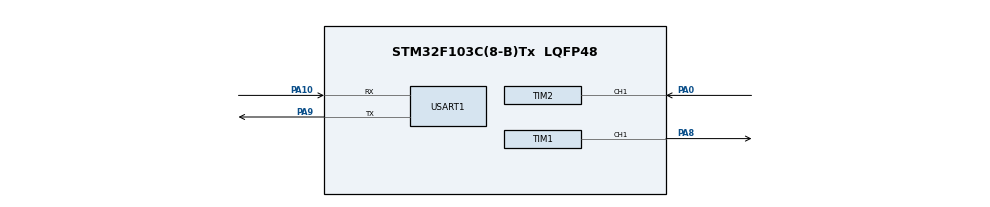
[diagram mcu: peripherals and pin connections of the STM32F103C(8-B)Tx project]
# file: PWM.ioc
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Mcu.Family=STM32F1
Mcu.Name=STM32F103C(8-B)Tx
Mcu.Package=LQFP48
NVIC.PriorityGroup=NVIC_PRIORITYGROUP_4
NVIC.TIM2_IRQn=true\:0\:0\:false\:false\:true\:true\:true\:true
PA0-WKUP.Signal=S_TIM2_CH1_ETR
PA10.Mode=Asynchronous
PA10.Signal=USART1_RX
PA13.Mode=Serial_Wire
PA13.Signal=SYS_JTMS-SWDIO
PA14.Mode=Serial_Wire
PA14.Signal=SYS_JTCK-SWCLK
PA8.Signal=S_TIM1_CH1
PA9.Mode=Asynchronous
PA9.Signal=USART1_TX
PD0-OSC_IN.Mode=HSE-External-Oscillator
PD0-OSC_IN.Signal=RCC_OSC_IN
PD1-OSC_OUT.Mode=HSE-External-Oscillator
PD1-OSC_OUT.Signal=RCC_OSC_OUT
ProjectManager.HeapSize=0x600
ProjectManager.StackSize=0x600
ProjectManager.TargetToolchain=MDK-ARM V5.32
RCC.APB1Freq_Value=8000000
RCC.APB2Freq_Value=8000000
SH.S_TIM1_CH1.0=TIM1_CH1,PWM Generation1 CH1
SH.S_TIM2_CH1_ETR.0=TIM2_CH1,PWM_Input_1
TIM1.Channel-PWM\ Generation1\ CH1=TIM_CHANNEL_1
TIM1.Period=999
TIM1.Prescaler=71
TIM2.Prescaler=71
USART1.VirtualMode=VM_ASYNC
board=custom

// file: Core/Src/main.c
/* USER CODE BEGIN Header */
/**
  ******************************************************************************
  * @file           : main.c
  * @brief          : Main program body
  ******************************************************************************
  * @attention
  *
  * Copyright (c) 2026 STMicroelectronics.
  * All rights reserved.
  *
  * This software is licensed under terms that can be found in the LICENSE file
  * in the root directory of this software component.
  * If no LICENSE file comes with this software, it is provided AS-IS.
  *
  ******************************************************************************
  */
/* USER CODE END Header */
#include "main.h"

/* USER CODE BEGIN Includes */
#include <stdio.h>
#include <string.h>
#include "mpu6050.h"

/* USER CODE END Includes */

TIM_HandleTypeDef htim1;
TIM_HandleTypeDef htim2;

UART_HandleTypeDef huart1;

/* USER CODE BEGIN PV */
// MPU6050 與 PID 相關變數
float Pitch = 0, Roll = 0;
float Target_Angle = -1.5f; // [修改] 根據實際重心微調中值 (正負 2.0 內調整)
float Kp = 38.0f;           // [調低] 減少噴射感
float Ki = 0.8f;            // [新增] 積分增益，用來站直
float Kd = 2.8f;            // [修改] 微調 Kd 增加穩定性
float Balance_PWM = 0;
float Last_Error = 0;
float Bias_Integral = 0;    // [新增] 積分累加變數

char msg[128];
float Steer_PWM = 0;
float Track_Speed = 100.0f; // [稍微調高] 確保轉向有力
uint32_t IC_Val1 = 0, IC_Val2 = 0;
float Frequency = 0, DutyCycle = 0, OnTime_ms = 0, OffTime_ms = 0, TotalPeriod_ms = 0;

uint8_t is_mpu6050_ok = 0; // [新增] 紀錄感測器是否正常啟動
/* USER CODE END PV */

void SystemClock_Config(void);
static void MX_GPIO_Init(void);
static void MX_TIM1_Init(void);
static void MX_TIM2_Init(void);
static void MX_USART1_UART_Init(void);
/* USER CODE BEGIN PFP */
void Motor_Control(int left_speed, int right_speed);
float Balance_Control(float Angle, float Target);
/* USER CODE END PFP */

/* USER CODE BEGIN 0 */
/**
  * @brief  直立平衡控制 (PID 演算法)
  * @param  Angle: 目前 Pitch 角度
  * @param  Target: 目標角度 (中性點)
  */
float Balance_Control(float Angle, float Target)
{
    float Error = Angle - Target;

    // 1. 積分累加 (Ki) - 只有在角度小於 30 度時才累積，避免翻車時積分暴走
    if (Angle < 30.0f && Angle > -30.0f) {
        Bias_Integral += Error;
    } else {
        Bias_Integral = 0; // 角度太大時清空積分
    }

    // 2. 限制積分上限 (Anti-Windup)
    if (Bias_Integral > 1000) Bias_Integral = 1000;
    if (Bias_Integral < -1000) Bias_Integral = -1000;

    // 3. PID 計算：Output = Kp*E + Ki*I + Kd*D
    float Output = Kp * Error + Ki * Bias_Integral + Kd * (Error - Last_Error);
    Last_Error = Error;

    return Output;
}

/**
  * @brief  控制馬達速度與方向 (安全限制與死區補償版)
  * @param  left_speed: 左輪速度 (-1000 到 1000)
  * @param  right_speed: 右輪速度 (-1000 到 1000)
  */
void Motor_Control(int left_speed, int right_speed)
{
    const int MAX_PWM = 600;
    const int DEAD_ZONE = 160; // [稍微調高] 確保基礎扭力足以轉彎

    // 傾倒保護：角度超過 70 度自動停機
    if (Pitch > 70.0f || Pitch < -70.0f) {
        left_speed = 0;
        right_speed = 0;
        Bias_Integral = 0; // 停機時清空積分
        HAL_GPIO_WritePin(GPIOB, GPIO_PIN_5, GPIO_PIN_RESET); // 進入待機
    } else {
        HAL_GPIO_WritePin(GPIOB, GPIO_PIN_5, GPIO_PIN_SET);   // 正常啟動

        // [新增] 死區補償：確保小角度也能推動馬達
        if (left_speed > 0) left_speed += DEAD_ZONE;
        else if (left_speed < 0) left_speed -= DEAD_ZONE;

        if (right_speed > 0) right_speed += DEAD_ZONE;
        else if (right_speed < 0) right_speed -= DEAD_ZONE;
    }

    // 方向控制與 PWM 設定
    if (left_speed >= 0) {
        HAL_GPIO_WritePin(GPIOB, GPIO_PIN_12, GPIO_PIN_SET);
        HAL_GPIO_WritePin(GPIOB, GPIO_PIN_13, GPIO_PIN_RESET);
    } else {
        HAL_GPIO_WritePin(GPIOB, GPIO_PIN_12, GPIO_PIN_RESET);
        HAL_GPIO_WritePin(GPIOB, GPIO_PIN_13, GPIO_PIN_SET);
        left_speed = -left_speed;
    }

    if (right_speed >= 0) {
        HAL_GPIO_WritePin(GPIOB, GPIO_PIN_14, GPIO_PIN_SET);
        HAL_GPIO_WritePin(GPIOB, GPIO_PIN_15, GPIO_PIN_RESET);
    } else {
        HAL_GPIO_WritePin(GPIOB, GPIO_PIN_14, GPIO_PIN_RESET);
        HAL_GPIO_WritePin(GPIOB, GPIO_PIN_15, GPIO_PIN_SET);
        right_speed = -right_speed;
    }

    if (left_speed > MAX_PWM) left_speed = MAX_PWM;
    if (right_speed > MAX_PWM) right_speed = MAX_PWM;

    __HAL_TIM_SET_COMPARE(&htim1, TIM_CHANNEL_1, left_speed);
    __HAL_TIM_SET_COMPARE(&htim1, TIM_CHANNEL_4, right_speed);
}
/* USER CODE END 0 */

int main(void)
{

  /* MCU Configuration--------------------------------------------------------*/

  /* Reset of all peripherals, Initializes the Flash interface and the Systick. */
  HAL_Init();

  /* Configure the system clock */
  SystemClock_Config();

  /* Initialize all configured peripherals */
  MX_GPIO_Init();
  MX_TIM1_Init();
  MX_TIM2_Init();
  MX_USART1_UART_Init();
  /* USER CODE BEGIN 2 */
  // [修改] 初始化 MPU6050 並紀錄結果
  if (MPU6050_Init() == 0) {
      is_mpu6050_ok = 1;
      sprintf(msg, "MPU6050 OK!\r\n");
      HAL_UART_Transmit(&huart1, (uint8_t*)msg, strlen(msg), 100);
  } else {
      is_mpu6050_ok = 0;
      sprintf(msg, "MPU6050 FAIL! ID error or bus stuck.\r\n");
      HAL_UART_Transmit(&huart1, (uint8_t*)msg, strlen(msg), 100);
      // 初始化失敗時，確保馬達處於安全狀態
      HAL_GPIO_WritePin(GPIOB, GPIO_PIN_5, GPIO_PIN_RESET);
  }

  /* 啟動 TIM1 的 PWM 輸出 */
  HAL_TIM_PWM_Start(&htim1, TIM_CHANNEL_1);
  HAL_TIM_PWM_Start(&htim1, TIM_CHANNEL_4);

  /* USER CODE END 2 */

  /* Infinite loop */
  /* USER CODE BEGIN WHILE */
  uint32_t last_tick = HAL_GetTick();
  while (1)
  {
    // [修改] 只有感測器正常時才進行 PID 控制
    if (is_mpu6050_ok && (HAL_GetTick() - last_tick >= 10)) {
        float dt = (HAL_GetTick() - last_tick) / 1000.0f;
        last_tick = HAL_GetTick();

        // 1. 讀取角度
        MPU6050_Get_Angle(&Pitch, &Roll, dt);

        // 2. 平衡控制 (PD 計算) - 加上負號修正方向
        Balance_PWM = -Balance_Control(Pitch, Target_Angle);

        // 3. 循跡邏輯 (讀取 PB10/PB11)
        uint8_t L_Sensor = HAL_GPIO_ReadPin(GPIOB, GPIO_PIN_10);
        uint8_t R_Sensor = HAL_GPIO_ReadPin(GPIOB, GPIO_PIN_11);

        float velocity_scale = 1.0f;

        if (L_Sensor == 0 && R_Sensor == 1) {
            Steer_PWM = -Track_Speed;
            velocity_scale = 0.85f; // [修改] 轉向時輕微減速即可 (打 85 折)
        } else if (L_Sensor == 1 && R_Sensor == 0) {
            Steer_PWM = Track_Speed;
            velocity_scale = 0.85f; // [修改] 轉向時輕微減速即可 (打 85 折)
        } else {
            Steer_PWM = 0;
            velocity_scale = 1.0f;
        }

        // 4. 輸出整合控制 (平衡 + 轉向)
        // 將 Balance_PWM 乘上縮放係數達成減速效果
        Motor_Control((int)(Balance_PWM * velocity_scale + Steer_PWM), (int)(Balance_PWM * velocity_scale - Steer_PWM));

        // 5. 定期串口輸出調試
        static int count = 0;
        if (count++ >= 20) {
            sprintf(msg, "Angle: %.2f | PWM: %d | Steer: %d\r\n", Pitch, (int)Balance_PWM, (int)Steer_PWM);
            HAL_UART_Transmit(&huart1, (uint8_t*)msg, strlen(msg), 10);
            count = 0;
        }
    } else if (!is_mpu6050_ok) {
        // 感測器異常時，強制停機保護
        Motor_Control(0, 0);
        HAL_GPIO_WritePin(GPIOB, GPIO_PIN_5, GPIO_PIN_RESET);
    }
    /* USER CODE END WHILE */

  }
}

void SystemClock_Config(void)
{
  RCC_OscInitTypeDef RCC_OscInitStruct = {0};
  RCC_ClkInitTypeDef RCC_ClkInitStruct = {0};

  /** Initializes the RCC Oscillators according to the specified parameters
  * in the RCC_OscInitTypeDef structure.
  */
  RCC_OscInitStruct.OscillatorType = RCC_OSCILLATORTYPE_HSI;
  RCC_OscInitStruct.HSIState = RCC_HSI_ON;
  RCC_OscInitStruct.HSICalibrationValue = RCC_HSICALIBRATION_DEFAULT;
  RCC_OscInitStruct.PLL.PLLState = RCC_PLL_NONE;
  if (HAL_RCC_OscConfig(&RCC_OscInitStruct) != HAL_OK)
  {
    Error_Handler();
  }

  /** Initializes the CPU, AHB and APB buses clocks
  */
  RCC_ClkInitStruct.ClockType = RCC_CLOCKTYPE_HCLK|RCC_CLOCKTYPE_SYSCLK
                              |RCC_CLOCKTYPE_PCLK1|RCC_CLOCKTYPE_PCLK2;
  RCC_ClkInitStruct.SYSCLKSource = RCC_SYSCLKSOURCE_HSI;
  RCC_ClkInitStruct.AHBCLKDivider = RCC_SYSCLK_DIV1;
  RCC_ClkInitStruct.APB1CLKDivider = RCC_HCLK_DIV1;
  RCC_ClkInitStruct.APB2CLKDivider = RCC_HCLK_DIV1;

  if (HAL_RCC_ClockConfig(&RCC_ClkInitStruct, FLASH_LATENCY_0) != HAL_OK)
  {
    Error_Handler();
  }
}

static void MX_TIM1_Init(void)
{

  TIM_MasterConfigTypeDef sMasterConfig = {0};
  TIM_OC_InitTypeDef sConfigOC = {0};
  TIM_BreakDeadTimeConfigTypeDef sBreakDeadTimeConfig = {0};

  htim1.Instance = TIM1;
  htim1.Init.Prescaler = 71;
  htim1.Init.CounterMode = TIM_COUNTERMODE_UP;
  htim1.Init.Period = 999;
  htim1.Init.ClockDivision = TIM_CLOCKDIVISION_DIV1;
  htim1.Init.RepetitionCounter = 0;
  htim1.Init.AutoReloadPreload = TIM_AUTORELOAD_PRELOAD_DISABLE;
  if (HAL_TIM_PWM_Init(&htim1) != HAL_OK)
  {
    Error_Handler();
  }
  sMasterConfig.MasterOutputTrigger = TIM_TRGO_RESET;
  sMasterConfig.MasterSlaveMode = TIM_MASTERSLAVEMODE_DISABLE;
  if (HAL_TIMEx_MasterConfigSynchronization(&htim1, &sMasterConfig) != HAL_OK)
  {
    Error_Handler();
  }
  sConfigOC.OCMode = TIM_OCMODE_PWM1;
  sConfigOC.Pulse = 0;
  sConfigOC.OCPolarity = TIM_OCPOLARITY_HIGH;
  sConfigOC.OCNPolarity = TIM_OCNPOLARITY_HIGH;
  sConfigOC.OCFastMode = TIM_OCFAST_DISABLE;
  sConfigOC.OCIdleState = TIM_OCIDLESTATE_RESET;
  sConfigOC.OCNIdleState = TIM_OCNIDLESTATE_RESET;
  if (HAL_TIM_PWM_ConfigChannel(&htim1, &sConfigOC, TIM_CHANNEL_1) != HAL_OK)
  {
    Error_Handler();
  }
  if (HAL_TIM_PWM_ConfigChannel(&htim1, &sConfigOC, TIM_CHANNEL_4) != HAL_OK)
  {
    Error_Handler();
  }
  sBreakDeadTimeConfig.OffStateRunMode = TIM_OSSR_DISABLE;
  sBreakDeadTimeConfig.OffStateIDLEMode = TIM_OSSI_DISABLE;
  sBreakDeadTimeConfig.LockLevel = TIM_LOCKLEVEL_OFF;
  sBreakDeadTimeConfig.DeadTime = 0;
  sBreakDeadTimeConfig.BreakState = TIM_BREAK_DISABLE;
  sBreakDeadTimeConfig.BreakPolarity = TIM_BREAKPOLARITY_HIGH;
  sBreakDeadTimeConfig.AutomaticOutput = TIM_AUTOMATICOUTPUT_DISABLE;
  if (HAL_TIMEx_ConfigBreakDeadTime(&htim1, &sBreakDeadTimeConfig) != HAL_OK)
  {
    Error_Handler();
  }
  HAL_TIM_MspPostInit(&htim1);

}

static void MX_TIM2_Init(void)
{

  TIM_SlaveConfigTypeDef sSlaveConfig = {0};
  TIM_IC_InitTypeDef sConfigIC = {0};
  TIM_MasterConfigTypeDef sMasterConfig = {0};

  htim2.Instance = TIM2;
  htim2.Init.Prescaler = 71;
  htim2.Init.CounterMode = TIM_COUNTERMODE_UP;
  htim2.Init.Period = 65535;
  htim2.Init.ClockDivision = TIM_CLOCKDIVISION_DIV1;
  htim2.Init.AutoReloadPreload = TIM_AUTORELOAD_PRELOAD_DISABLE;
  if (HAL_TIM_IC_Init(&htim2) != HAL_OK)
  {
    Error_Handler();
  }
  sSlaveConfig.SlaveMode = TIM_SLAVEMODE_RESET;
  sSlaveConfig.InputTrigger = TIM_TS_TI1FP1;
  sSlaveConfig.TriggerPolarity = TIM_INPUTCHANNELPOLARITY_RISING;
  sSlaveConfig.TriggerPrescaler = TIM_ICPSC_DIV1;
  sSlaveConfig.TriggerFilter = 0;
  if (HAL_TIM_SlaveConfigSynchro(&htim2, &sSlaveConfig) != HAL_OK)
  {
    Error_Handler();
  }
  sConfigIC.ICPolarity = TIM_INPUTCHANNELPOLARITY_RISING;
  sConfigIC.ICSelection = TIM_ICSELECTION_DIRECTTI;
  sConfigIC.ICPrescaler = TIM_ICPSC_DIV1;
  sConfigIC.ICFilter = 0;
  if (HAL_TIM_IC_ConfigChannel(&htim2, &sConfigIC, TIM_CHANNEL_1) != HAL_OK)
  {
    Error_Handler();
  }
  sConfigIC.ICPolarity = TIM_INPUTCHANNELPOLARITY_FALLING;
  sConfigIC.ICSelection = TIM_ICSELECTION_INDIRECTTI;
  if (HAL_TIM_IC_ConfigChannel(&htim2, &sConfigIC, TIM_CHANNEL_2) != HAL_OK)
  {
    Error_Handler();
  }
  sMasterConfig.MasterOutputTrigger = TIM_TRGO_RESET;
  sMasterConfig.MasterSlaveMode = TIM_MASTERSLAVEMODE_DISABLE;
  if (HAL_TIMEx_MasterConfigSynchronization(&htim2, &sMasterConfig) != HAL_OK)
  {
    Error_Handler();
  }

}

static void MX_USART1_UART_Init(void)
{

  huart1.Instance = USART1;
  huart1.Init.BaudRate = 115200;
  huart1.Init.WordLength = UART_WORDLENGTH_8B;
  huart1.Init.StopBits = UART_STOPBITS_1;
  huart1.Init.Parity = UART_PARITY_NONE;
  huart1.Init.Mode = UART_MODE_TX_RX;
  huart1.Init.HwFlowCtl = UART_HWCONTROL_NONE;
  huart1.Init.OverSampling = UART_OVERSAMPLING_16;
  if (HAL_UART_Init(&huart1) != HAL_OK)
  {
    Error_Handler();
  }

}

static void MX_GPIO_Init(void)
{
  GPIO_InitTypeDef GPIO_InitStruct = {0};

  /* GPIO Ports Clock Enable */
  __HAL_RCC_GPIOD_CLK_ENABLE();
  __HAL_RCC_GPIOA_CLK_ENABLE();
  __HAL_RCC_GPIOB_CLK_ENABLE();

  /*Configure GPIO pin Output Level */
  HAL_GPIO_WritePin(GPIOB, GPIO_PIN_5|GPIO_PIN_12|GPIO_PIN_13|GPIO_PIN_14
                          |GPIO_PIN_15, GPIO_PIN_RESET);

  /*Configure GPIO pins : PB5 PB12 PB13 PB14 PB15 */
  GPIO_InitStruct.Pin = GPIO_PIN_5|GPIO_PIN_12|GPIO_PIN_13|GPIO_PIN_14
                          |GPIO_PIN_15;
  GPIO_InitStruct.Mode = GPIO_MODE_OUTPUT_PP;
  GPIO_InitStruct.Pull = GPIO_NOPULL;
  GPIO_InitStruct.Speed = GPIO_SPEED_FREQ_LOW;
  HAL_GPIO_Init(GPIOB, &GPIO_InitStruct);

  /*Configure GPIO pins : PB10 PB11 */
  GPIO_InitStruct.Pin = GPIO_PIN_10|GPIO_PIN_11;
  GPIO_InitStruct.Mode = GPIO_MODE_INPUT;
  GPIO_InitStruct.Pull = GPIO_PULLUP;
  HAL_GPIO_Init(GPIOB, &GPIO_InitStruct);

}

/* USER CODE BEGIN 4 */
void HAL_TIM_IC_CaptureCallback(TIM_HandleTypeDef *htim)
{
  if (htim->Instance == TIM2)
  {
    if (htim->Channel == HAL_TIM_ACTIVE_CHANNEL_1)
    {
      IC_Val1 = HAL_TIM_ReadCapturedValue(htim, TIM_CHANNEL_1);

      if (IC_Val1 != 0)
      {
        // 1. 計算頻率
        Frequency = 1000000.0f / IC_Val1;

        // 2. 計算總週期 (將 us 換算成 ms)
        TotalPeriod_ms = (float)IC_Val1 / 1000.0f;

        // 3. 計算導通時間 (ms)
        OnTime_ms = (float)IC_Val2 / 1000.0f;

        // 4. 計算關閉時間 (ms)
        OffTime_ms = TotalPeriod_ms - OnTime_ms;

        // 5. 計算工作週期 (%)
        DutyCycle = (float)IC_Val2 * 100.0f / IC_Val1;
      }
    }
    else if (htim->Channel == HAL_TIM_ACTIVE_CHANNEL_2)
    {
      IC_Val2 = HAL_TIM_ReadCapturedValue(htim, TIM_CHANNEL_2);
    }
  }
}

/* USER CODE END 4 */

void Error_Handler(void)
{
  __disable_irq();
  while (1)
  {
  }
}
